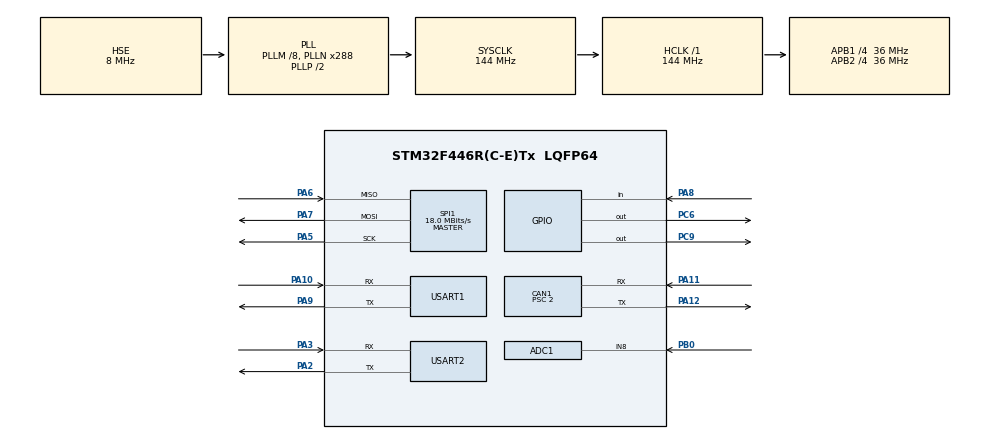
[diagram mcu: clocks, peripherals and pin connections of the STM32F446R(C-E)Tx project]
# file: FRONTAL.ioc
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ADC1.Channel-0\#ChannelRegularConversion=ADC_CHANNEL_8
ADC1.ContinuousConvMode=ENABLE
ADC1.DMAContinuousRequests=ENABLE
ADC1.NbrOfConversion=1
ADC1.NbrOfConversionFlag=1
ADC1.Rank-0\#ChannelRegularConversion=1
ADC1.SamplingTime-0\#ChannelRegularConversion=ADC_SAMPLETIME_3CYCLES
ADC1.ScanConvMode=ENABLE
ADC1.master=1
CAN1.AWUM=ENABLE
CAN1.BS1=CAN_BS1_12TQ
CAN1.BS2=CAN_BS2_5TQ
CAN1.CalculateTimeQuantum=55.55555555555556
CAN1.Prescaler=2
Dma.ADC1.0.Direction=DMA_PERIPH_TO_MEMORY
Dma.ADC1.0.FIFOMode=DMA_FIFOMODE_DISABLE
Dma.ADC1.0.Instance=DMA2_Stream0
Dma.ADC1.0.MemDataAlignment=DMA_MDATAALIGN_HALFWORD
Dma.ADC1.0.MemInc=DMA_MINC_ENABLE
Dma.ADC1.0.Mode=DMA_NORMAL
Dma.ADC1.0.PeriphDataAlignment=DMA_PDATAALIGN_HALFWORD
Dma.ADC1.0.PeriphInc=DMA_PINC_DISABLE
Dma.ADC1.0.Priority=DMA_PRIORITY_LOW
Dma.Request0=ADC1
Mcu.Family=STM32F4
Mcu.Name=STM32F446R(C-E)Tx
Mcu.Package=LQFP64
NVIC.ADC_IRQn=true\:0\:0\:false\:true\:true\:5\:true
NVIC.CAN1_RX0_IRQn=true\:0\:0\:false\:true\:true\:2\:true
NVIC.CAN1_RX1_IRQn=true\:0\:0\:false\:true\:true\:3\:true
NVIC.CAN1_SCE_IRQn=true\:0\:0\:false\:true\:true\:4\:true
NVIC.CAN1_TX_IRQn=true\:0\:0\:false\:true\:true\:1\:true
NVIC.DMA2_Stream0_IRQn=true\:0\:0\:false\:false\:true\:false
NVIC.PriorityGroup=NVIC_PRIORITYGROUP_4
NVIC.TIM1_UP_TIM10_IRQn=true\:0\:0\:false\:true\:true\:10\:true
NVIC.TIM2_IRQn=true\:0\:0\:false\:true\:true\:9\:true
NVIC.TIM4_IRQn=true\:0\:0\:false\:false\:true\:true
NVIC.TIM5_IRQn=true\:0\:0\:false\:true\:true\:8\:true
NVIC.TIM6_DAC_IRQn=true\:0\:0\:false\:true\:true\:7\:true
NVIC.TIM7_IRQn=true\:0\:0\:false\:true\:true\:6\:true
NVIC.USART1_IRQn=true\:0\:0\:false\:true\:true\:11\:true
NVIC.USART2_IRQn=true\:0\:0\:false\:false\:true\:true
PA10.Mode=Asynchronous
PA10.Signal=USART1_RX
PA11.GPIO_PuPd=GPIO_PULLUP
PA11.Mode=Master
PA11.Signal=CAN1_RX
PA12.Mode=Master
PA12.Signal=CAN1_TX
PA2.Mode=Asynchronous
PA2.Signal=USART2_TX
PA3.Mode=Asynchronous
PA3.Signal=USART2_RX
PA5.Mode=Full_Duplex_Master
PA5.Signal=SPI1_SCK
PA6.Mode=Full_Duplex_Master
PA6.Signal=SPI1_MISO
PA7.Mode=Full_Duplex_Master
PA7.Signal=SPI1_MOSI
PA8.Signal=GPIO_Input
PA9.Mode=Asynchronous
PA9.Signal=USART1_TX
PB0.Signal=ADCx_IN8
PC6.GPIO_Speed=GPIO_SPEED_FREQ_VERY_HIGH
PC6.PinState=GPIO_PIN_SET
PC6.Signal=GPIO_Output
PC9.Signal=GPIO_Output
PH0-OSC_IN.Mode=HSE-External-Clock-Source
PH0-OSC_IN.Signal=RCC_OSC_IN
PH1-OSC_OUT.Mode=HSE-External-Clock-Source
PH1-OSC_OUT.Signal=RCC_OSC_OUT
ProjectManager.HeapSize=0x200
ProjectManager.StackSize=0x400
ProjectManager.TargetToolchain=SW4STM32
RCC.AHBFreq_Value=144000000
RCC.APB1CLKDivider=RCC_HCLK_DIV4
RCC.APB1Freq_Value=36000000
RCC.APB1TimFreq_Value=72000000
RCC.APB2CLKDivider=RCC_HCLK_DIV4
RCC.APB2Freq_Value=36000000
RCC.APB2TimFreq_Value=72000000
RCC.CortexFreq_Value=144000000
RCC.HCLKFreq_Value=144000000
RCC.HSE_VALUE=8000000
RCC.PLLM=8
RCC.PLLN=288
RCC.PLLSourceVirtual=RCC_PLLSOURCE_HSE
RCC.SYSCLKFreq_VALUE=144000000
RCC.SYSCLKSource=RCC_SYSCLKSOURCE_PLLCLK
RCC.USBFreq_Value=144000000
RCC.VCOOutputFreq_Value=288000000
SH.ADCx_IN8.0=ADC1_IN8,IN8
SPI1.BaudRatePrescaler=SPI_BAUDRATEPRESCALER_2
SPI1.CalculateBaudRate=18.0 MBits/s
SPI1.Direction=SPI_DIRECTION_2LINES
SPI1.Mode=SPI_MODE_MASTER
SPI1.VirtualType=VM_MASTER
TIM10.Period=140
TIM10.Prescaler=3600
TIM2.Period=1000
TIM2.Prescaler=36
TIM3.Period=65500
TIM3.Prescaler=18
TIM4.Period=2000
TIM4.Prescaler=3600
TIM5.Period=2000
TIM5.Prescaler=36
TIM6.Period=2000
TIM6.Prescaler=3600
TIM7.Period=60
TIM7.Prescaler=3600
USART1.VirtualMode=VM_ASYNC
USART2.VirtualMode=VM_ASYNC
VP_TIM10_VS_ClockSourceINT.Mode=Enable_Timer
VP_TIM2_VS_ClockSourceINT.Mode=Internal
VP_TIM2_VS_ClockSourceITR.Mode=TriggerSource_ITR0
VP_TIM3_VS_ClockSourceINT.Mode=Internal
VP_TIM4_VS_ClockSourceINT.Mode=Internal
VP_TIM5_VS_ClockSourceINT.Mode=Internal
VP_TIM6_VS_ClockSourceINT.Mode=Enable_Timer
VP_TIM7_VS_ClockSourceINT.Mode=Enable_Timer
board=custom

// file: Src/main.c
/**
  ******************************************************************************
  * @file           : main.c
  * @brief          : Main program body
  ******************************************************************************
  ** This notice applies to any and all portions of this file
  * that are not between comment pairs USER CODE BEGIN and
  * USER CODE END. Other portions of this file, whether
  * inserted by the user or by software development tools
  * are owned by their respective copyright owners.
  *
  * COPYRIGHT(c) 2019 STMicroelectronics
  *
  * Redistribution and use in source and binary forms, with or without modification,
  * are permitted provided that the following conditions are met:
  *   1. Redistributions of source code must retain the above copyright notice,
  *      this list of conditions and the following disclaimer.
  *   2. Redistributions in binary form must reproduce the above copyright notice,
  *      this list of conditions and the following disclaimer in the documentation
  *      and/or other materials provided with the distribution.
  *   3. Neither the name of STMicroelectronics nor the names of its contributors
  *      may be used to endorse or promote products derived from this software
  *      without specific prior written permission.
  *
  * THIS SOFTWARE IS PROVIDED BY THE COPYRIGHT HOLDERS AND CONTRIBUTORS "AS IS"
  * AND ANY EXPRESS OR IMPLIED WARRANTIES, INCLUDING, BUT NOT LIMITED TO, THE
  * IMPLIED WARRANTIES OF MERCHANTABILITY AND FITNESS FOR A PARTICULAR PURPOSE ARE
  * DISCLAIMED. IN NO EVENT SHALL THE COPYRIGHT HOLDER OR CONTRIBUTORS BE LIABLE
  * FOR ANY DIRECT, INDIRECT, INCIDENTAL, SPECIAL, EXEMPLARY, OR CONSEQUENTIAL
  * DAMAGES (INCLUDING, BUT NOT LIMITED TO, PROCUREMENT OF SUBSTITUTE GOODS OR
  * SERVICES; LOSS OF USE, DATA, OR PROFITS; OR BUSINESS INTERRUPTION) HOWEVER
  * CAUSED AND ON ANY THEORY OF LIABILITY, WHETHER IN CONTRACT, STRICT LIABILITY,
  * OR TORT (INCLUDING NEGLIGENCE OR OTHERWISE) ARISING IN ANY WAY OUT OF THE USE
  * OF THIS SOFTWARE, EVEN IF ADVISED OF THE POSSIBILITY OF SUCH DAMAGE.
  *
  ******************************************************************************
  */
#include "main.h"
#include "stm32f4xx_hal.h"

/* USER CODE BEGIN Includes */
#include "Eagle_TRT.h"
#include "string.h"
#include "stdio.h"
#include "stdlib.h"
#include <inttypes.h>
#include "stm32f4xx_hal_gpio.h"
#include "stm32f4xx_it.h"
#include <math.h>
/* USER CODE END Includes */

ADC_HandleTypeDef hadc1;
DMA_HandleTypeDef hdma_adc1;

CAN_HandleTypeDef hcan1;

SPI_HandleTypeDef hspi1;

TIM_HandleTypeDef htim2;
TIM_HandleTypeDef htim3;
TIM_HandleTypeDef htim4;
TIM_HandleTypeDef htim5;
TIM_HandleTypeDef htim6;
TIM_HandleTypeDef htim7;
TIM_HandleTypeDef htim10;

UART_HandleTypeDef huart1;
UART_HandleTypeDef huart2;

/* USER CODE BEGIN PV */
/* Private variables ---------------------------------------------------------*/
extern can_stc can;
extern imu_stc imu;
extern enc_stc enc;
extern pot_stc pot_1;
extern pot_stc pot_2;
extern pot_stc pot_3;

CAN_FilterTypeDef sFilter;
uint32_t valMax0, valMin0, val0rang;
uint32_t ADC_buffer[3], val[3];
char txt[100];
int flag = 0;
int timer_factor = 2;
int command_flag = 0;
int steer_flag = 0;

TIM_HandleTypeDef a_TimerInstance2 = {.Instance = TIM2};
TIM_HandleTypeDef a_TimerInstance3 = {.Instance = TIM3};
TIM_HandleTypeDef a_TimerInstance4 = {.Instance = TIM4};
TIM_HandleTypeDef a_TimerInstance5 = {.Instance = TIM5};
TIM_HandleTypeDef a_TimerInstance6 = {.Instance = TIM6};
TIM_HandleTypeDef a_TimerInstance7 = {.Instance = TIM7};
TIM_HandleTypeDef a_TimerInstance10 = {.Instance = TIM10};

gps_struct gps_main;
/* USER CODE END PV */

void SystemClock_Config(void);
static void MX_GPIO_Init(void);
static void MX_DMA_Init(void);
static void MX_USART2_UART_Init(void);
static void MX_CAN1_Init(void);
static void MX_SPI1_Init(void);
static void MX_ADC1_Init(void);
static void MX_USART1_UART_Init(void);
static void MX_TIM2_Init(void);
static void MX_TIM3_Init(void);
static void MX_TIM4_Init(void);
static void MX_TIM5_Init(void);
static void MX_TIM6_Init(void);
static void MX_TIM7_Init(void);
static void MX_TIM10_Init(void);
static void MX_NVIC_Init(void);

/* USER CODE BEGIN 0 */
void HAL_ADC_ConvCpltCallback(ADC_HandleTypeDef* hadc)
{
  pot_1.val = ADC_buffer[0];
  pot_2.val = ADC_buffer[1];
  pot_3.val = ADC_buffer[2];
  /*int txt_1[100];
  sprintf(txt_1, "sterzo: %d %d %d\r\n", pot_1.val, pot_2.val, pot_3.val);
  HAL_UART_Transmit(&huart2, (uint8_t*)txt_1, strlen(txt_1), 10);*/
}

int steer_enc_prescaler;

/* USER CODE END 0 */

int main(void)
{

  /* MCU Configuration----------------------------------------------------------*/

  /* Reset of all peripherals, Initializes the Flash interface and the Systick. */
  HAL_Init();

  /* Configure the system clock */
  SystemClock_Config();

  /* Initialize all configured peripherals */
  MX_GPIO_Init();
  MX_DMA_Init();
  MX_USART2_UART_Init();
  MX_CAN1_Init();
  MX_SPI1_Init();
  MX_ADC1_Init();
  MX_USART1_UART_Init();
  MX_TIM2_Init();
  MX_TIM3_Init();
  MX_TIM4_Init();
  MX_TIM5_Init();
  MX_TIM6_Init();
  MX_TIM7_Init();
  MX_TIM10_Init();

  /* Initialize interrupts */
  MX_NVIC_Init();
  /* USER CODE BEGIN 2 */

  sFilter.FilterMode = CAN_FILTERMODE_IDMASK;
  sFilter.FilterIdLow = 0;
  sFilter.FilterIdHigh = 0;
  sFilter.FilterMaskIdHigh = 0;
  sFilter.FilterMaskIdLow = 0;
  sFilter.FilterFIFOAssignment = CAN_FILTER_FIFO0;
  sFilter.FilterBank = 0;
  sFilter.FilterScale  = CAN_FILTERSCALE_16BIT;
  sFilter.FilterActivation = ENABLE;
  HAL_CAN_ConfigFilter(&hcan1, &sFilter);

  HAL_CAN_Start(&hcan1);

  HAL_CAN_ActivateNotification(&hcan1, CAN1_RX0_IRQn);
  HAL_CAN_ActivateNotification(&hcan1, CAN1_RX1_IRQn);
  /* USER CODE END 2 */

  /* Infinite loop */
  /* USER CODE BEGIN WHILE */
  can.hcan=&hcan1;
  // can initialization //

  // imu initialization //
  imu.GPIOx_InUse=GPIOC;
  imu.GPIO_Pin_InUse=GPIO_PIN_9;
  imu.GPIOx_NotInUse=GPIOA;
  imu.GPIO_Pin_NotInUse=GPIO_PIN_8;
  imu.hspi = &hspi1;
  HAL_GPIO_WritePin(GPIOA, GPIO_PIN_8, GPIO_PIN_SET); ///CS_G to 1
  HAL_GPIO_WritePin(GPIOC, GPIO_PIN_9, GPIO_PIN_SET); ///CS_XM to 1

  if(gps_init(&huart1,&gps_main)==0){
	  //--error--//
  }

  steer_enc_prescaler = htim3.Init.Period;
  steer_enc_prescaler /= 3;
  steer_enc_prescaler /= 20;
  steer_enc_prescaler += 40;
  enc.steer_enc_prescaler = steer_enc_prescaler;

	pot_2.max = 4060;
	pot_2.min = 2350;
	pot_2.range = abs(pot_2.max - pot_2.min);

  enc.dx_wheel = 0;
  enc.interrupt_flag = 0;
  enc.TimerInstance = &a_TimerInstance3;
  enc.average_speed = 0;
  enc.wheel_diameter = 4064;
  enc.refresh = 1000;
  enc.data_size = 14;
  enc.clock_period = (36 / htim3.Init.Prescaler);

  //enc.htim = &htim2;

  HAL_TIM_Base_Start(&htim2);
  HAL_TIM_Base_Start(&htim3);
  //HAL_TIM_Base_Start(&htim4);
  //HAL_TIM_Base_Start(&htim5);
  //HAL_TIM_Base_Start(&htim6);
  HAL_TIM_Base_Start(&htim7);
  HAL_TIM_Base_Start(&htim10);

  HAL_TIM_Base_Start_IT(&htim2);
  HAL_TIM_Base_Start_IT(&htim3);
  //HAL_TIM_Base_Start_IT(&htim4);
  //HAL_TIM_Base_Start_IT(&htim5);
  //HAL_TIM_Base_Start_IT(&htim6);
  HAL_TIM_Base_Start_IT(&htim7);
  HAL_TIM_Base_Start_IT(&htim10);

  __HAL_TIM_SET_COUNTER(&a_TimerInstance2, 0);
  __HAL_TIM_SET_COUNTER(&a_TimerInstance3, 0);
  //__HAL_TIM_SET_COUNTER(&a_TimerInstance4, 0);
  //__HAL_TIM_SET_COUNTER(&a_TimerInstance5, 0);
  //__HAL_TIM_SET_COUNTER(&a_TimerInstance6, 0);
  __HAL_TIM_SET_COUNTER(&a_TimerInstance7, 0);
  __HAL_TIM_SET_COUNTER(&a_TimerInstance10, 0);

  //HAL_Delay(1000);
  LSMD9S0_accel_init(&imu);
  LSMD9S0_gyro_init(&imu);
  LSMD9S0_check(&imu);

  while (1)
  {

  /* USER CODE END WHILE */

  /* USER CODE BEGIN 3 */

/*
	  //sprintf(txt, "%d\r\n", (int)enc.average_speed);
	  sprintf(txt, "%d\t%d\t%d\r\n", (int)imu.X_A_axis, (int)imu.Y_A_axis, (int)imu.Z_A_axis);
	  HAL_UART_Transmit(&huart2, (uint8_t*)txt, strlen(txt), 10);*/
	  HAL_ADC_Start_DMA(&hadc1, ADC_buffer, 3);

  }
  /* USER CODE END 3 */

}

void SystemClock_Config(void)
{

  RCC_OscInitTypeDef RCC_OscInitStruct;
  RCC_ClkInitTypeDef RCC_ClkInitStruct;

    /**Configure the main internal regulator output voltage
    */
  __HAL_RCC_PWR_CLK_ENABLE();

  __HAL_PWR_VOLTAGESCALING_CONFIG(PWR_REGULATOR_VOLTAGE_SCALE1);

    /**Initializes the CPU, AHB and APB busses clocks
    */
  RCC_OscInitStruct.OscillatorType = RCC_OSCILLATORTYPE_HSE;
  RCC_OscInitStruct.HSEState = RCC_HSE_BYPASS;
  RCC_OscInitStruct.PLL.PLLState = RCC_PLL_ON;
  RCC_OscInitStruct.PLL.PLLSource = RCC_PLLSOURCE_HSE;
  RCC_OscInitStruct.PLL.PLLM = 8;
  RCC_OscInitStruct.PLL.PLLN = 288;
  RCC_OscInitStruct.PLL.PLLP = RCC_PLLP_DIV2;
  RCC_OscInitStruct.PLL.PLLQ = 2;
  RCC_OscInitStruct.PLL.PLLR = 2;
  if (HAL_RCC_OscConfig(&RCC_OscInitStruct) != HAL_OK)
  {
    _Error_Handler(__FILE__, __LINE__);
  }

    /**Initializes the CPU, AHB and APB busses clocks
    */
  RCC_ClkInitStruct.ClockType = RCC_CLOCKTYPE_HCLK|RCC_CLOCKTYPE_SYSCLK
                              |RCC_CLOCKTYPE_PCLK1|RCC_CLOCKTYPE_PCLK2;
  RCC_ClkInitStruct.SYSCLKSource = RCC_SYSCLKSOURCE_PLLCLK;
  RCC_ClkInitStruct.AHBCLKDivider = RCC_SYSCLK_DIV1;
  RCC_ClkInitStruct.APB1CLKDivider = RCC_HCLK_DIV4;
  RCC_ClkInitStruct.APB2CLKDivider = RCC_HCLK_DIV4;

  if (HAL_RCC_ClockConfig(&RCC_ClkInitStruct, FLASH_LATENCY_4) != HAL_OK)
  {
    _Error_Handler(__FILE__, __LINE__);
  }

    /**Configure the Systick interrupt time
    */
  HAL_SYSTICK_Config(HAL_RCC_GetHCLKFreq()/1000);

    /**Configure the Systick
    */
  HAL_SYSTICK_CLKSourceConfig(SYSTICK_CLKSOURCE_HCLK);

  /* SysTick_IRQn interrupt configuration */
  HAL_NVIC_SetPriority(SysTick_IRQn, 0, 0);
}

/**
  * @brief NVIC Configuration.
  * @retval None
  */
static void MX_NVIC_Init(void)
{
  /* CAN1_TX_IRQn interrupt configuration */
  HAL_NVIC_SetPriority(CAN1_TX_IRQn, 0, 0);
  HAL_NVIC_EnableIRQ(CAN1_TX_IRQn);
  /* CAN1_RX0_IRQn interrupt configuration */
  HAL_NVIC_SetPriority(CAN1_RX0_IRQn, 0, 0);
  HAL_NVIC_EnableIRQ(CAN1_RX0_IRQn);
  /* CAN1_RX1_IRQn interrupt configuration */
  HAL_NVIC_SetPriority(CAN1_RX1_IRQn, 0, 0);
  HAL_NVIC_EnableIRQ(CAN1_RX1_IRQn);
  /* CAN1_SCE_IRQn interrupt configuration */
  HAL_NVIC_SetPriority(CAN1_SCE_IRQn, 0, 0);
  HAL_NVIC_EnableIRQ(CAN1_SCE_IRQn);
  /* ADC_IRQn interrupt configuration */
  HAL_NVIC_SetPriority(ADC_IRQn, 0, 0);
  HAL_NVIC_EnableIRQ(ADC_IRQn);
  /* TIM7_IRQn interrupt configuration */
  HAL_NVIC_SetPriority(TIM7_IRQn, 0, 0);
  HAL_NVIC_EnableIRQ(TIM7_IRQn);
  /* TIM6_DAC_IRQn interrupt configuration */
  HAL_NVIC_SetPriority(TIM6_DAC_IRQn, 0, 0);
  HAL_NVIC_EnableIRQ(TIM6_DAC_IRQn);
  /* TIM5_IRQn interrupt configuration */
  HAL_NVIC_SetPriority(TIM5_IRQn, 0, 0);
  HAL_NVIC_EnableIRQ(TIM5_IRQn);
  /* TIM2_IRQn interrupt configuration */
  HAL_NVIC_SetPriority(TIM2_IRQn, 0, 0);
  HAL_NVIC_EnableIRQ(TIM2_IRQn);
  /* TIM1_UP_TIM10_IRQn interrupt configuration */
  HAL_NVIC_SetPriority(TIM1_UP_TIM10_IRQn, 0, 0);
  HAL_NVIC_EnableIRQ(TIM1_UP_TIM10_IRQn);
  /* USART1_IRQn interrupt configuration */
  HAL_NVIC_SetPriority(USART1_IRQn, 0, 0);
  HAL_NVIC_EnableIRQ(USART1_IRQn);
}

/* ADC1 init function */
static void MX_ADC1_Init(void)
{

  ADC_ChannelConfTypeDef sConfig;

    /**Configure the global features of the ADC (Clock, Resolution, Data Alignment and number of conversion)
    */
  hadc1.Instance = ADC1;
  hadc1.Init.ClockPrescaler = ADC_CLOCK_SYNC_PCLK_DIV2;
  hadc1.Init.Resolution = ADC_RESOLUTION_12B;
  hadc1.Init.ScanConvMode = ENABLE;
  hadc1.Init.ContinuousConvMode = ENABLE;
  hadc1.Init.DiscontinuousConvMode = DISABLE;
  hadc1.Init.ExternalTrigConvEdge = ADC_EXTERNALTRIGCONVEDGE_NONE;
  hadc1.Init.ExternalTrigConv = ADC_SOFTWARE_START;
  hadc1.Init.DataAlign = ADC_DATAALIGN_RIGHT;
  hadc1.Init.NbrOfConversion = 1;
  hadc1.Init.DMAContinuousRequests = ENABLE;
  hadc1.Init.EOCSelection = ADC_EOC_SINGLE_CONV;
  if (HAL_ADC_Init(&hadc1) != HAL_OK)
  {
    _Error_Handler(__FILE__, __LINE__);
  }

    /**Configure for the selected ADC regular channel its corresponding rank in the sequencer and its sample time.
    */
  sConfig.Channel = ADC_CHANNEL_8;
  sConfig.Rank = 1;
  sConfig.SamplingTime = ADC_SAMPLETIME_3CYCLES;
  if (HAL_ADC_ConfigChannel(&hadc1, &sConfig) != HAL_OK)
  {
    _Error_Handler(__FILE__, __LINE__);
  }

}

/* CAN1 init function */
static void MX_CAN1_Init(void)
{

  hcan1.Instance = CAN1;
  hcan1.Init.Prescaler = 2;
  hcan1.Init.Mode = CAN_MODE_NORMAL;
  hcan1.Init.SyncJumpWidth = CAN_SJW_1TQ;
  hcan1.Init.TimeSeg1 = CAN_BS1_12TQ;
  hcan1.Init.TimeSeg2 = CAN_BS2_5TQ;
  hcan1.Init.TimeTriggeredMode = DISABLE;
  hcan1.Init.AutoBusOff = DISABLE;
  hcan1.Init.AutoWakeUp = ENABLE;
  hcan1.Init.AutoRetransmission = DISABLE;
  hcan1.Init.ReceiveFifoLocked = DISABLE;
  hcan1.Init.TransmitFifoPriority = DISABLE;
  if (HAL_CAN_Init(&hcan1) != HAL_OK)
  {
    _Error_Handler(__FILE__, __LINE__);
  }

}

/* SPI1 init function */
static void MX_SPI1_Init(void)
{

  /* SPI1 parameter configuration*/
  hspi1.Instance = SPI1;
  hspi1.Init.Mode = SPI_MODE_MASTER;
  hspi1.Init.Direction = SPI_DIRECTION_2LINES;
  hspi1.Init.DataSize = SPI_DATASIZE_8BIT;
  hspi1.Init.CLKPolarity = SPI_POLARITY_LOW;
  hspi1.Init.CLKPhase = SPI_PHASE_1EDGE;
  hspi1.Init.NSS = SPI_NSS_SOFT;
  hspi1.Init.BaudRatePrescaler = SPI_BAUDRATEPRESCALER_2;
  hspi1.Init.FirstBit = SPI_FIRSTBIT_MSB;
  hspi1.Init.TIMode = SPI_TIMODE_DISABLE;
  hspi1.Init.CRCCalculation = SPI_CRCCALCULATION_DISABLE;
  hspi1.Init.CRCPolynomial = 10;
  if (HAL_SPI_Init(&hspi1) != HAL_OK)
  {
    _Error_Handler(__FILE__, __LINE__);
  }

}

/* TIM2 init function */
static void MX_TIM2_Init(void)
{

  TIM_ClockConfigTypeDef sClockSourceConfig;
  TIM_SlaveConfigTypeDef sSlaveConfig;
  TIM_MasterConfigTypeDef sMasterConfig;

  htim2.Instance = TIM2;
  htim2.Init.Prescaler = 36;
  htim2.Init.CounterMode = TIM_COUNTERMODE_UP;
  htim2.Init.Period = 1000;
  htim2.Init.ClockDivision = TIM_CLOCKDIVISION_DIV1;
  if (HAL_TIM_Base_Init(&htim2) != HAL_OK)
  {
    _Error_Handler(__FILE__, __LINE__);
  }

  sClockSourceConfig.ClockSource = TIM_CLOCKSOURCE_INTERNAL;
  if (HAL_TIM_ConfigClockSource(&htim2, &sClockSourceConfig) != HAL_OK)
  {
    _Error_Handler(__FILE__, __LINE__);
  }

  sSlaveConfig.SlaveMode = TIM_SLAVEMODE_DISABLE;
  sSlaveConfig.InputTrigger = TIM_TS_ITR0;
  if (HAL_TIM_SlaveConfigSynchronization(&htim2, &sSlaveConfig) != HAL_OK)
  {
    _Error_Handler(__FILE__, __LINE__);
  }

  sMasterConfig.MasterOutputTrigger = TIM_TRGO_RESET;
  sMasterConfig.MasterSlaveMode = TIM_MASTERSLAVEMODE_DISABLE;
  if (HAL_TIMEx_MasterConfigSynchronization(&htim2, &sMasterConfig) != HAL_OK)
  {
    _Error_Handler(__FILE__, __LINE__);
  }

}

/* TIM3 init function */
static void MX_TIM3_Init(void)
{

  TIM_ClockConfigTypeDef sClockSourceConfig;
  TIM_MasterConfigTypeDef sMasterConfig;

  htim3.Instance = TIM3;
  htim3.Init.Prescaler = 18;
  htim3.Init.CounterMode = TIM_COUNTERMODE_UP;
  htim3.Init.Period = 65500;
  htim3.Init.ClockDivision = TIM_CLOCKDIVISION_DIV1;
  if (HAL_TIM_Base_Init(&htim3) != HAL_OK)
  {
    _Error_Handler(__FILE__, __LINE__);
  }

  sClockSourceConfig.ClockSource = TIM_CLOCKSOURCE_INTERNAL;
  if (HAL_TIM_ConfigClockSource(&htim3, &sClockSourceConfig) != HAL_OK)
  {
    _Error_Handler(__FILE__, __LINE__);
  }

  sMasterConfig.MasterOutputTrigger = TIM_TRGO_RESET;
  sMasterConfig.MasterSlaveMode = TIM_MASTERSLAVEMODE_DISABLE;
  if (HAL_TIMEx_MasterConfigSynchronization(&htim3, &sMasterConfig) != HAL_OK)
  {
    _Error_Handler(__FILE__, __LINE__);
  }

}

/* TIM4 init function */
static void MX_TIM4_Init(void)
{

  TIM_ClockConfigTypeDef sClockSourceConfig;
  TIM_MasterConfigTypeDef sMasterConfig;

  htim4.Instance = TIM4;
  htim4.Init.Prescaler = 3600;
  htim4.Init.CounterMode = TIM_COUNTERMODE_UP;
  htim4.Init.Period = 2000;
  htim4.Init.ClockDivision = TIM_CLOCKDIVISION_DIV1;
  if (HAL_TIM_Base_Init(&htim4) != HAL_OK)
  {
    _Error_Handler(__FILE__, __LINE__);
  }

  sClockSourceConfig.ClockSource = TIM_CLOCKSOURCE_INTERNAL;
  if (HAL_TIM_ConfigClockSource(&htim4, &sClockSourceConfig) != HAL_OK)
  {
    _Error_Handler(__FILE__, __LINE__);
  }

  sMasterConfig.MasterOutputTrigger = TIM_TRGO_RESET;
  sMasterConfig.MasterSlaveMode = TIM_MASTERSLAVEMODE_DISABLE;
  if (HAL_TIMEx_MasterConfigSynchronization(&htim4, &sMasterConfig) != HAL_OK)
  {
    _Error_Handler(__FILE__, __LINE__);
  }

}

/* TIM5 init function */
static void MX_TIM5_Init(void)
{

  TIM_ClockConfigTypeDef sClockSourceConfig;
  TIM_MasterConfigTypeDef sMasterConfig;

  htim5.Instance = TIM5;
  htim5.Init.Prescaler = 36;
  htim5.Init.CounterMode = TIM_COUNTERMODE_UP;
  htim5.Init.Period = 2000;
  htim5.Init.ClockDivision = TIM_CLOCKDIVISION_DIV1;
  if (HAL_TIM_Base_Init(&htim5) != HAL_OK)
  {
    _Error_Handler(__FILE__, __LINE__);
  }

  sClockSourceConfig.ClockSource = TIM_CLOCKSOURCE_INTERNAL;
  if (HAL_TIM_ConfigClockSource(&htim5, &sClockSourceConfig) != HAL_OK)
  {
    _Error_Handler(__FILE__, __LINE__);
  }

  sMasterConfig.MasterOutputTrigger = TIM_TRGO_RESET;
  sMasterConfig.MasterSlaveMode = TIM_MASTERSLAVEMODE_DISABLE;
  if (HAL_TIMEx_MasterConfigSynchronization(&htim5, &sMasterConfig) != HAL_OK)
  {
    _Error_Handler(__FILE__, __LINE__);
  }

}

/* TIM6 init function */
static void MX_TIM6_Init(void)
{

  TIM_MasterConfigTypeDef sMasterConfig;

  htim6.Instance = TIM6;
  htim6.Init.Prescaler = 3600;
  htim6.Init.CounterMode = TIM_COUNTERMODE_UP;
  htim6.Init.Period = 2000;
  if (HAL_TIM_Base_Init(&htim6) != HAL_OK)
  {
    _Error_Handler(__FILE__, __LINE__);
  }

  sMasterConfig.MasterOutputTrigger = TIM_TRGO_RESET;
  sMasterConfig.MasterSlaveMode = TIM_MASTERSLAVEMODE_DISABLE;
  if (HAL_TIMEx_MasterConfigSynchronization(&htim6, &sMasterConfig) != HAL_OK)
  {
    _Error_Handler(__FILE__, __LINE__);
  }

}

/* TIM7 init function */
static void MX_TIM7_Init(void)
{

  TIM_MasterConfigTypeDef sMasterConfig;

  htim7.Instance = TIM7;
  htim7.Init.Prescaler = 36;
  htim7.Init.CounterMode = TIM_COUNTERMODE_UP;
  htim7.Init.Period = 2000;
  if (HAL_TIM_Base_Init(&htim7) != HAL_OK)
  {
    _Error_Handler(__FILE__, __LINE__);
  }

  sMasterConfig.MasterOutputTrigger = TIM_TRGO_RESET;
  sMasterConfig.MasterSlaveMode = TIM_MASTERSLAVEMODE_DISABLE;
  if (HAL_TIMEx_MasterConfigSynchronization(&htim7, &sMasterConfig) != HAL_OK)
  {
    _Error_Handler(__FILE__, __LINE__);
  }

}

/* TIM10 init function */
static void MX_TIM10_Init(void)
{

  htim10.Instance = TIM10;
  htim10.Init.Prescaler = 36;
  htim10.Init.CounterMode = TIM_COUNTERMODE_UP;
  htim10.Init.Period = 500;
  htim10.Init.ClockDivision = TIM_CLOCKDIVISION_DIV1;
  if (HAL_TIM_Base_Init(&htim10) != HAL_OK)
  {
    _Error_Handler(__FILE__, __LINE__);
  }

}

/* USART1 init function */
static void MX_USART1_UART_Init(void)
{

  huart1.Instance = USART1;
  huart1.Init.BaudRate = 115200;
  huart1.Init.WordLength = UART_WORDLENGTH_8B;
  huart1.Init.StopBits = UART_STOPBITS_1;
  huart1.Init.Parity = UART_PARITY_NONE;
  huart1.Init.Mode = UART_MODE_TX_RX;
  huart1.Init.HwFlowCtl = UART_HWCONTROL_NONE;
  huart1.Init.OverSampling = UART_OVERSAMPLING_16;
  if (HAL_UART_Init(&huart1) != HAL_OK)
  {
    _Error_Handler(__FILE__, __LINE__);
  }

}

/* USART2 init function */
static void MX_USART2_UART_Init(void)
{

  huart2.Instance = USART2;
  huart2.Init.BaudRate = 115200;
  huart2.Init.WordLength = UART_WORDLENGTH_8B;
  huart2.Init.StopBits = UART_STOPBITS_1;
  huart2.Init.Parity = UART_PARITY_NONE;
  huart2.Init.Mode = UART_MODE_TX_RX;
  huart2.Init.HwFlowCtl = UART_HWCONTROL_NONE;
  huart2.Init.OverSampling = UART_OVERSAMPLING_16;
  if (HAL_UART_Init(&huart2) != HAL_OK)
  {
    _Error_Handler(__FILE__, __LINE__);
  }

}

static void MX_DMA_Init(void)
{
  /* DMA controller clock enable */
  __HAL_RCC_DMA2_CLK_ENABLE();

  /* DMA interrupt init */
  /* DMA2_Stream0_IRQn interrupt configuration */
  HAL_NVIC_SetPriority(DMA2_Stream0_IRQn, 0, 0);
  HAL_NVIC_EnableIRQ(DMA2_Stream0_IRQn);

}

/** Configure pins as
        * Analog
        * Input
        * Output
        * EVENT_OUT
        * EXTI
*/
static void MX_GPIO_Init(void)
{

  GPIO_InitTypeDef GPIO_InitStruct;

  /* GPIO Ports Clock Enable */
  __HAL_RCC_GPIOH_CLK_ENABLE();
  __HAL_RCC_GPIOA_CLK_ENABLE();
  __HAL_RCC_GPIOB_CLK_ENABLE();
  __HAL_RCC_GPIOC_CLK_ENABLE();

  /*Configure GPIO pin Output Level */
  HAL_GPIO_WritePin(GPIOC, GPIO_PIN_6, GPIO_PIN_SET);

  /*Configure GPIO pin Output Level */
  HAL_GPIO_WritePin(GPIOC, GPIO_PIN_9, GPIO_PIN_RESET);

  /*Configure GPIO pin Output Level */
  HAL_GPIO_WritePin(GPIOA, GPIO_PIN_8, GPIO_PIN_RESET);

  /*Configure GPIO pin : PC6 */
  GPIO_InitStruct.Pin = GPIO_PIN_6;
  GPIO_InitStruct.Mode = GPIO_MODE_OUTPUT_PP;
  GPIO_InitStruct.Pull = GPIO_NOPULL;
  GPIO_InitStruct.Speed = GPIO_SPEED_FREQ_VERY_HIGH;
  HAL_GPIO_Init(GPIOC, &GPIO_InitStruct);

  /*Configure GPIO pin : PC8 */
  GPIO_InitStruct.Pin = GPIO_PIN_8;
  GPIO_InitStruct.Mode = GPIO_MODE_INPUT;
  GPIO_InitStruct.Pull = GPIO_NOPULL;
  HAL_GPIO_Init(GPIOC, &GPIO_InitStruct);

  /*Configure GPIO pin : PC9 */
  GPIO_InitStruct.Pin = GPIO_PIN_9;
  GPIO_InitStruct.Mode = GPIO_MODE_OUTPUT_PP;
  GPIO_InitStruct.Pull = GPIO_NOPULL;
  GPIO_InitStruct.Speed = GPIO_SPEED_FREQ_LOW;
  HAL_GPIO_Init(GPIOC, &GPIO_InitStruct);

  /*Configure GPIO pin : PA8 */
  GPIO_InitStruct.Pin = GPIO_PIN_8;
  GPIO_InitStruct.Mode = GPIO_MODE_OUTPUT_PP;
  GPIO_InitStruct.Pull = GPIO_NOPULL;
  GPIO_InitStruct.Speed = GPIO_SPEED_FREQ_LOW;
  HAL_GPIO_Init(GPIOA, &GPIO_InitStruct);

  /*Configure GPIO pin : PB8 */
  GPIO_InitStruct.Pin = GPIO_PIN_8;
  GPIO_InitStruct.Mode = GPIO_MODE_INPUT;
  GPIO_InitStruct.Pull = GPIO_NOPULL;
  HAL_GPIO_Init(GPIOB, &GPIO_InitStruct);

}

/* USER CODE BEGIN 4 */
void HAL_UART_RxCpltCallback(UART_HandleTypeDef *huart){
	if(huart == &huart1){
		gps_read_it(huart,&gps_main);
	}
}

void HAL_UART_TxCpltCallback(UART_HandleTypeDef *huart){
	if(huart == &huart2){
		print_it(&huart2);
	}
}

void HAL_CAN_RxFifo0FullCallback(CAN_HandleTypeDef *hcan){
	///CALIBRATION CODE///
	  int idsave = CAN_Receive(&can);
	  //201/202

	  if(idsave == 0x55 || idsave == 0x201){
		  if(can.dataRx[0] == 0x51 || can.dataRx[0] == 0x03 || can.dataRx[0] == 0x04 || can.dataRx[0] == 0x05 || can.dataRx[0] == 0x08 || can.dataRx[0] == 0x0A || can.dataRx[0] == 0x0B){
			  command_flag = 1;
			  idsave = 0;
		  }
	  }
	  if(idsave == 0xA0 || idsave == 0xAA || idsave == 0x181){
		  if(can.dataRx[0] == 0x03 || can.dataRx[0] == 0x04 || can.dataRx[0] == 0x05 || can.dataRx[0] == 0x08 || can.dataRx[0] == 0xD8){
			  command_flag = 1;
			  idsave = 0;
		  }
	  }

	  if (idsave == 0xBB){
		//  sprintf(val0, "APPS1: %d \r\n", idsave);  //use "%lu" for long, "%d" for int
		  //		  HAL_UART_Transmit(&huart2, (uint8_t*)val0, strlen(val0), 10);
		  if ((can.dataRx[0] == 2) && (can.dataRx[1] == 0)){
			set_min(&pot_2);
			  //CheckControl[0] = 1;
			  can.dataTx[0] = 2;
			  can.dataTx[1] = 0;
			  can.dataTx[2] = 0;
			  can.dataTx[3] = 0;
			  can.dataTx[4] = 0;
			  can.dataTx[5] = 0;
			  can.dataTx[6] = 0;
			  can.dataTx[7] = 0;
			  can.id = 0xBC;
			  can.size = 8;
			  for(int i = 0; i < 200; i++){
			  //HAL_Delay(50);
				  CAN_Send(&can);
			  }
		  }
		  if ((can.dataRx[0] == 2) && (can.dataRx[1] == 1)){
			set_max(&pot_3);
			  //CheckControl[1] = 1;
			  can.dataTx[0] = 2;
			  can.dataTx[1] = 1;
			  can.dataTx[2] = 0;
			  can.dataTx[3] = 0;
			  can.dataTx[4] = 0;
			  can.dataTx[5] = 0;
			  can.dataTx[6] = 0;
			  can.dataTx[7] = 0;
			  can.id = 0xBC;
			  can.size = 8;
			  //HAL_Delay(50);
			  for(int i = 0; i < 200; i++){
				  CAN_Send(&can);
			  }

		  }
		  //val0rang = abs(valMax0 - valMin0);
		pot_3.range = abs(pot_3.max - pot_3.min);
	 }
}

void HAL_TIM_PeriodElapsedCallback(TIM_HandleTypeDef *htim){

	if(htim == &htim10){
		switch (flag){
			case 0:

				break;
			case 1:
				//encoder_tim_interrupt(&enc);
				LSMD9S0_accel_read(&imu);
				break;
			case 2:
				//encoder_tim_interrupt(&enc);
				break;
			case 3:
				break;
			case 4:
				LSMD9S0_gyro_read(&imu);
				break;
			case 5:
				break;
			case 6:

				if(steer_flag == 0){
				calc_pot_value(&pot_2);

					can.dataTx[0] = 2;
					can.dataTx[1] = pot_2.val_100;
					can.dataTx[2] = 0;
					can.dataTx[3] = 0;
					can.dataTx[4] = 0;
					can.dataTx[5] = 0;
					can.dataTx[6] = 0;
					can.dataTx[7] = 0;
					can.id = 0xC0;
					can.size = 8;
					CAN_Send(&can);
					steer_flag = 1;
				}
				else{
					steer_flag = 0;
				}
				break;
			case 7:
				break;
		}
		if(flag == 7){
			flag = 0;
		}
		else{
			flag  ++;
		}
	}

	if(htim == &htim7){
		encoder_tim_interrupt(&enc);
	}
}

/* USER CODE END 4 */

void _Error_Handler(char *file, int line)
{
  while(1)
  {
  }
}

/************************ (C) COPYRIGHT STMicroelectronics *****END OF FILE****/
